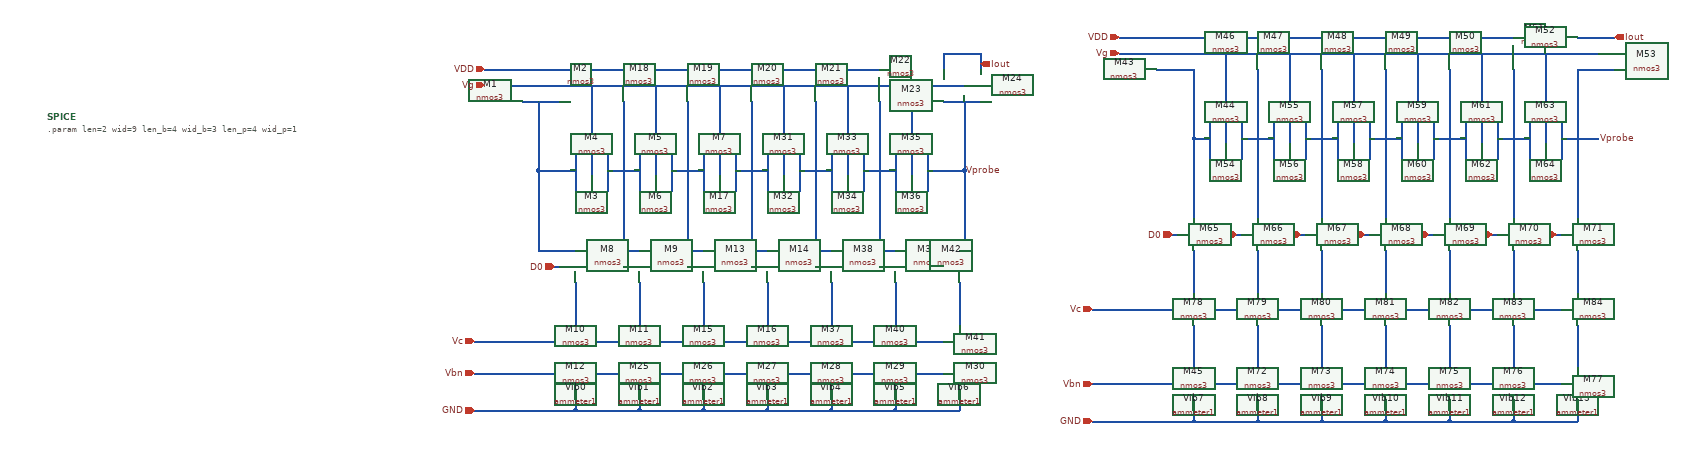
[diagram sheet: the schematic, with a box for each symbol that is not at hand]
v {xschem version=3.4.8RC file_version=1.3}
G {}
K {}
V {}
S {}
F {}
E {}
N 470 -350 480 -350 {lab=D0}
N 590 -350 600 -350 {lab=D1}
N 710 -350 720 -350 {lab=D2}
N 830 -350 840 -350 {lab=D3}
N 510 -320 510 -300 {lab=#net1}
N 630 -320 630 -300 {lab=#net2}
N 750 -320 750 -300 {lab=#net3}
N 870 -320 870 -300 {lab=#net4}
N 430 -150 480 -150 {lab=Vbn}
N 480 -150 600 -150 {lab=Vbn}
N 600 -150 720 -150 {lab=Vbn}
N 720 -150 840 -150 {lab=Vbn}
N 440 -690 450 -690 {lab=Vg}
N 410 -660 480 -660 {lab=#net5}
N 1230 -690 1240 -690 {lab=Vg}
N 1200 -750 1270 -750 {lab=Iout}
N 1200 -660 1270 -660 {lab=Vprobe}
N 450 -690 630 -690 {lab=Vg}
N 630 -690 750 -690 {lab=Vg}
N 1110 -690 1230 -690 {lab=Vg}
N 540 -530 540 -520 {lab=Vg}
N 540 -690 540 -530 {lab=Vg}
N 660 -690 660 -530 {lab=Vg}
N 1140 -530 1140 -520 {lab=Vg}
N 1140 -690 1140 -530 {lab=Vg}
N 510 -560 510 -490 {lab=#net5}
N 570 -560 570 -490 {lab=#net6}
N 1110 -560 1110 -490 {lab=#net7}
N 1170 -560 1170 -490 {lab=Vprobe}
N 440 -660 440 -530 {lab=#net5}
N 440 -530 510 -530 {lab=#net5}
N 570 -530 630 -530 {lab=#net6}
N 600 -660 600 -530 {lab=#net6}
N 690 -530 750 -530 {lab=#net8}
N 720 -660 720 -530 {lab=#net8}
N 1170 -530 1240 -530 {lab=Vprobe}
N 1240 -660 1240 -530 {lab=Vprobe}
N 440 -530 440 -380 {lab=#net5}
N 440 -380 510 -380 {lab=#net5}
N 600 -530 600 -380 {lab=#net6}
N 600 -380 630 -380 {lab=#net6}
N 720 -530 720 -380 {lab=#net8}
N 720 -380 750 -380 {lab=#net8}
N 1240 -530 1240 -380 {lab=Vprobe}
N 1230 -380 1240 -380 {lab=Vprobe}
N 950 -350 960 -350 {lab=D4}
N 990 -320 990 -300 {lab=#net9}
N 1070 -350 1080 -350 {lab=D5}
N 1110 -320 1110 -300 {lab=#net10}
N 1190 -350 1200 -350 {lab=D6}
N 1230 -320 1230 -300 {lab=#net11}
N 750 -690 870 -690 {lab=Vg}
N 870 -690 990 -690 {lab=Vg}
N 990 -690 1110 -690 {lab=Vg}
N 780 -530 780 -520 {lab=Vg}
N 750 -560 750 -490 {lab=#net8}
N 810 -560 810 -490 {lab=#net12}
N 810 -530 870 -530 {lab=#net12}
N 900 -530 900 -520 {lab=Vg}
N 870 -560 870 -490 {lab=#net12}
N 930 -560 930 -490 {lab=#net13}
N 930 -530 990 -530 {lab=#net13}
N 1020 -530 1020 -520 {lab=Vg}
N 990 -560 990 -490 {lab=#net13}
N 1050 -560 1050 -490 {lab=#net7}
N 1050 -530 1110 -530 {lab=#net7}
N 840 -660 840 -530 {lab=#net12}
N 840 -530 840 -380 {lab=#net12}
N 840 -380 870 -380 {lab=#net12}
N 960 -660 960 -530 {lab=#net13}
N 960 -530 960 -380 {lab=#net13}
N 960 -380 990 -380 {lab=#net13}
N 1080 -660 1080 -530 {lab=#net7}
N 1080 -530 1080 -380 {lab=#net7}
N 1080 -380 1110 -380 {lab=#net7}
N 840 -150 960 -150 {lab=Vbn}
N 960 -150 1080 -150 {lab=Vbn}
N 1080 -150 1200 -150 {lab=Vbn}
N 780 -690 780 -530 {lab=Vg}
N 900 -690 900 -530 {lab=Vg}
N 1020 -690 1020 -530 {lab=Vg}
N 630 -560 630 -490 {lab=#net6}
N 690 -560 690 -490 {lab=#net8}
N 660 -530 660 -520 {lab=Vg}
N 410 -720 480 -720 {lab=VDD}
N 480 -720 600 -720 {lab=VDD}
N 600 -720 720 -720 {lab=VDD}
N 720 -720 840 -720 {lab=VDD}
N 840 -720 960 -720 {lab=VDD}
N 960 -720 1080 -720 {lab=VDD}
N 340 -720 410 -720 {lab=VDD}
N 1110 -80 1230 -80 {lab=GND}
N 990 -80 1110 -80 {lab=GND}
N 870 -80 990 -80 {lab=GND}
N 750 -80 870 -80 {lab=GND}
N 630 -80 750 -80 {lab=GND}
N 510 -80 630 -80 {lab=GND}
N 320 -80 510 -80 {lab=GND}
N 320 -150 430 -150 {lab=Vbn}
N 1200 -750 1200 -720 {lab=Iout}
N 1270 -750 1270 -720 {lab=Iout}
N 340 -690 440 -690 {lab=Vg}
N 510 -120 510 -100 {lab=#net14}
N 510 -90 510 -80 {lab=GND}
N 630 -120 630 -100 {lab=#net15}
N 630 -90 630 -80 {lab=GND}
N 750 -120 750 -100 {lab=#net16}
N 750 -90 750 -80 {lab=GND}
N 870 -120 870 -100 {lab=#net17}
N 870 -90 870 -80 {lab=GND}
N 990 -120 990 -100 {lab=#net18}
N 990 -90 990 -80 {lab=GND}
N 1110 -120 1110 -100 {lab=#net19}
N 1110 -90 1110 -80 {lab=GND}
N 1230 -120 1230 -100 {lab=#net20}
N 1230 -90 1230 -80 {lab=GND}
N 1230 -300 1230 -270 {lab=#net11}
N 1110 -300 1110 -270 {lab=#net10}
N 990 -300 990 -270 {lab=#net9}
N 870 -300 870 -270 {lab=#net4}
N 750 -300 750 -270 {lab=#net3}
N 630 -300 630 -270 {lab=#net2}
N 510 -300 510 -270 {lab=#net1}
N 510 -270 510 -240 {lab=#net1}
N 630 -270 630 -240 {lab=#net2}
N 750 -270 750 -240 {lab=#net3}
N 870 -270 870 -240 {lab=#net4}
N 990 -270 990 -240 {lab=#net9}
N 1110 -270 1110 -240 {lab=#net10}
N 1230 -270 1230 -240 {lab=#net11}
N 320 -210 480 -210 {lab=Vc}
N 480 -210 600 -210 {lab=Vc}
N 600 -210 720 -210 {lab=Vc}
N 720 -210 840 -210 {lab=Vc}
N 840 -210 960 -210 {lab=Vc}
N 960 -210 1080 -210 {lab=Vc}
N 1080 -210 1200 -210 {lab=Vc}
N 1630 -410 1640 -410 {lab=D0}
N 1750 -410 1760 -410 {lab=D1}
N 1870 -410 1880 -410 {lab=D2}
N 1990 -410 2000 -410 {lab=D3}
N 1590 -130 1640 -130 {lab=Vbn}
N 1640 -130 1760 -130 {lab=Vbn}
N 1760 -130 1880 -130 {lab=Vbn}
N 1880 -130 2000 -130 {lab=Vbn}
N 1630 -750 1640 -750 {lab=Vg}
N 1600 -720 1670 -720 {lab=#net1}
N 2420 -750 2430 -750 {lab=Vg}
N 2390 -780 2460 -780 {lab=Iout}
N 2390 -720 2460 -720 {lab=Vprobe}
N 1640 -750 1820 -750 {lab=Vg}
N 1820 -750 1940 -750 {lab=Vg}
N 2300 -750 2420 -750 {lab=Vg}
N 1730 -590 1730 -580 {lab=Vg}
N 1730 -750 1730 -590 {lab=Vg}
N 1850 -750 1850 -590 {lab=Vg}
N 2330 -590 2330 -580 {lab=Vg}
N 2330 -750 2330 -590 {lab=Vg}
N 1700 -620 1700 -550 {lab=#net1}
N 1760 -620 1760 -550 {lab=#net2}
N 2300 -620 2300 -550 {lab=#net3}
N 2360 -620 2360 -550 {lab=Vprobe}
N 1670 -720 1670 -590 {lab=#net1}
N 1760 -590 1820 -590 {lab=#net2}
N 1790 -720 1790 -590 {lab=#net2}
N 1880 -590 1940 -590 {lab=#net4}
N 1910 -720 1910 -590 {lab=#net4}
N 2360 -590 2430 -590 {lab=Vprobe}
N 1670 -590 1670 -440 {lab=#net1}
N 1790 -590 1790 -440 {lab=#net2}
N 1910 -590 1910 -440 {lab=#net4}
N 2390 -590 2390 -440 {lab=Vprobe}
N 2110 -410 2120 -410 {lab=D4}
N 2230 -410 2240 -410 {lab=D5}
N 2350 -410 2360 -410 {lab=D6}
N 1940 -750 2060 -750 {lab=Vg}
N 2060 -750 2180 -750 {lab=Vg}
N 2180 -750 2300 -750 {lab=Vg}
N 1970 -590 1970 -580 {lab=Vg}
N 1940 -620 1940 -550 {lab=#net4}
N 2000 -620 2000 -550 {lab=#net5}
N 2000 -590 2060 -590 {lab=#net5}
N 2090 -590 2090 -580 {lab=Vg}
N 2060 -620 2060 -550 {lab=#net5}
N 2120 -620 2120 -550 {lab=#net6}
N 2120 -590 2180 -590 {lab=#net6}
N 2210 -590 2210 -580 {lab=Vg}
N 2180 -620 2180 -550 {lab=#net6}
N 2240 -620 2240 -550 {lab=#net3}
N 2240 -590 2300 -590 {lab=#net3}
N 2030 -720 2030 -590 {lab=#net5}
N 2030 -590 2030 -440 {lab=#net5}
N 2150 -720 2150 -590 {lab=#net6}
N 2150 -590 2150 -440 {lab=#net6}
N 2270 -720 2270 -590 {lab=#net3}
N 2270 -590 2270 -440 {lab=#net3}
N 2000 -130 2120 -130 {lab=Vbn}
N 2120 -130 2240 -130 {lab=Vbn}
N 2240 -130 2360 -130 {lab=Vbn}
N 1970 -750 1970 -590 {lab=Vg}
N 2090 -750 2090 -590 {lab=Vg}
N 2210 -750 2210 -590 {lab=Vg}
N 1820 -620 1820 -550 {lab=#net2}
N 1880 -620 1880 -550 {lab=#net4}
N 1850 -590 1850 -580 {lab=Vg}
N 1600 -780 1670 -780 {lab=VDD}
N 1670 -780 1790 -780 {lab=VDD}
N 1790 -780 1910 -780 {lab=VDD}
N 1910 -780 2030 -780 {lab=VDD}
N 2030 -780 2150 -780 {lab=VDD}
N 2150 -780 2270 -780 {lab=VDD}
N 1530 -780 1600 -780 {lab=VDD}
N 2270 -60 2390 -60 {lab=GND}
N 2150 -60 2270 -60 {lab=GND}
N 2030 -60 2150 -60 {lab=GND}
N 1910 -60 2030 -60 {lab=GND}
N 1790 -60 1910 -60 {lab=GND}
N 1670 -60 1790 -60 {lab=GND}
N 1480 -60 1670 -60 {lab=GND}
N 1480 -130 1590 -130 {lab=Vbn}
N 1530 -750 1630 -750 {lab=Vg}
N 1670 -100 1670 -80 {lab=#net7}
N 1670 -70 1670 -60 {lab=GND}
N 1790 -100 1790 -80 {lab=#net8}
N 1790 -70 1790 -60 {lab=GND}
N 1910 -100 1910 -80 {lab=#net9}
N 1910 -70 1910 -60 {lab=GND}
N 2030 -100 2030 -80 {lab=#net10}
N 2030 -70 2030 -60 {lab=GND}
N 2150 -100 2150 -80 {lab=#net11}
N 2150 -70 2150 -60 {lab=GND}
N 2270 -100 2270 -80 {lab=#net12}
N 2270 -70 2270 -60 {lab=GND}
N 2390 -100 2390 -80 {lab=#net13}
N 2390 -70 2390 -60 {lab=GND}
N 1480 -270 1640 -270 {lab=Vc}
N 1640 -270 1760 -270 {lab=Vc}
N 1760 -270 1880 -270 {lab=Vc}
N 1880 -270 2000 -270 {lab=Vc}
N 2000 -270 2120 -270 {lab=Vc}
N 2120 -270 2240 -270 {lab=Vc}
N 2240 -270 2360 -270 {lab=Vc}
N 2390 -380 2390 -300 {lab=#net14}
N 2270 -380 2270 -300 {lab=#net15}
N 2150 -380 2150 -300 {lab=#net16}
N 2030 -380 2030 -300 {lab=#net17}
N 1910 -380 1910 -300 {lab=#net18}
N 1790 -380 1790 -300 {lab=#net19}
N 1670 -380 1670 -300 {lab=#net20}
N 1670 -240 1670 -160 {lab=#net21}
N 1790 -240 1790 -160 {lab=#net22}
N 1910 -240 1910 -160 {lab=#net23}
N 2030 -240 2030 -160 {lab=#net24}
N 2150 -240 2150 -160 {lab=#net25}
N 2270 -240 2270 -160 {lab=#net26}
N 2390 -240 2390 -160 {lab=#net27}
N 2390 -720 2390 -590 {lab=Vprobe}
N 1670 -590 1700 -590 {lab=#net1}
C {madvlsi/nmos3.sym} 410 -690 2 0 {name=M1
L=\{len\}
W=\{wid\}
body=GND
nf=1
mult=1
ad="'int((nf+1)/2) * W/nf * 0.29'" 
pd="'2*int((nf+1)/2) * (W/nf + 0.29)'"
as="'int((nf+2)/2) * W/nf * 0.29'" 
ps="'2*int((nf+2)/2) * (W/nf + 0.29)'"
nrd="'0.29 / W'" nrs="'0.29 / W'"
sa=0 sb=0 sd=0
model=nfet_01v8
spiceprefix=X
}
C {madvlsi/nmos3.sym} 540 -560 3 0 {name=M4
L=\{len\}
W=\{wid\}
body=GND
nf=1
mult=1
ad="'int((nf+1)/2) * W/nf * 0.29'" 
pd="'2*int((nf+1)/2) * (W/nf + 0.29)'"
as="'int((nf+2)/2) * W/nf * 0.29'" 
ps="'2*int((nf+2)/2) * (W/nf + 0.29)'"
nrd="'0.29 / W'" nrs="'0.29 / W'"
sa=0 sb=0 sd=0
model=nfet_01v8
spiceprefix=X
}
C {madvlsi/nmos3.sym} 510 -150 0 0 {name=M12
L=\{len_b\}
W=\{wid_b\}
body=GND
nf=1
mult=1
ad="'int((nf+1)/2) * W/nf * 0.29'" 
pd="'2*int((nf+1)/2) * (W/nf + 0.29)'"
as="'int((nf+2)/2) * W/nf * 0.29'" 
ps="'2*int((nf+2)/2) * (W/nf + 0.29)'"
nrd="'0.29 / W'" nrs="'0.29 / W'"
sa=0 sb=0 sd=0
model=nfet_01v8
spiceprefix=X
}
C {madvlsi/nmos3.sym} 480 -690 0 0 {name=M2
L=\{len\}
W=\{wid\}
body=GND
nf=1
mult=1
ad="'int((nf+1)/2) * W/nf * 0.29'" 
pd="'2*int((nf+1)/2) * (W/nf + 0.29)'"
as="'int((nf+2)/2) * W/nf * 0.29'" 
ps="'2*int((nf+2)/2) * (W/nf + 0.29)'"
nrd="'0.29 / W'" nrs="'0.29 / W'"
sa=0 sb=0 sd=0
model=nfet_01v8
spiceprefix=X
}
C {madvlsi/nmos3.sym} 600 -690 2 0 {name=M18
L=\{len\}
W=\{wid\}
body=GND
nf=1
mult=1
ad="'int((nf+1)/2) * W/nf * 0.29'" 
pd="'2*int((nf+1)/2) * (W/nf + 0.29)'"
as="'int((nf+2)/2) * W/nf * 0.29'" 
ps="'2*int((nf+2)/2) * (W/nf + 0.29)'"
nrd="'0.29 / W'" nrs="'0.29 / W'"
sa=0 sb=0 sd=0
model=nfet_01v8
spiceprefix=X
}
C {madvlsi/nmos3.sym} 720 -690 2 0 {name=M19
L=\{len\}
W=\{wid\}
body=GND
nf=1
mult=1
ad="'int((nf+1)/2) * W/nf * 0.29'" 
pd="'2*int((nf+1)/2) * (W/nf + 0.29)'"
as="'int((nf+2)/2) * W/nf * 0.29'" 
ps="'2*int((nf+2)/2) * (W/nf + 0.29)'"
nrd="'0.29 / W'" nrs="'0.29 / W'"
sa=0 sb=0 sd=0
model=nfet_01v8
spiceprefix=X
}
C {madvlsi/nmos3.sym} 840 -690 2 0 {name=M20
L=\{len\}
W=\{wid\}
body=GND
nf=1
mult=1
ad="'int((nf+1)/2) * W/nf * 0.29'" 
pd="'2*int((nf+1)/2) * (W/nf + 0.29)'"
as="'int((nf+2)/2) * W/nf * 0.29'" 
ps="'2*int((nf+2)/2) * (W/nf + 0.29)'"
nrd="'0.29 / W'" nrs="'0.29 / W'"
sa=0 sb=0 sd=0
model=nfet_01v8
spiceprefix=X
}
C {madvlsi/nmos3.sym} 960 -690 2 0 {name=M21
L=\{len\}
W=\{wid\}
body=GND
nf=1
mult=1
ad="'int((nf+1)/2) * W/nf * 0.29'" 
pd="'2*int((nf+1)/2) * (W/nf + 0.29)'"
as="'int((nf+2)/2) * W/nf * 0.29'" 
ps="'2*int((nf+2)/2) * (W/nf + 0.29)'"
nrd="'0.29 / W'" nrs="'0.29 / W'"
sa=0 sb=0 sd=0
model=nfet_01v8
spiceprefix=X
}
C {madvlsi/nmos3.sym} 1080 -690 2 0 {name=M22
L=\{len\}
W=\{wid\}
body=GND
nf=1
mult=1
ad="'int((nf+1)/2) * W/nf * 0.29'" 
pd="'2*int((nf+1)/2) * (W/nf + 0.29)'"
as="'int((nf+2)/2) * W/nf * 0.29'" 
ps="'2*int((nf+2)/2) * (W/nf + 0.29)'"
nrd="'0.29 / W'" nrs="'0.29 / W'"
sa=0 sb=0 sd=0
model=nfet_01v8
spiceprefix=X
}
C {madvlsi/nmos3.sym} 1200 -690 2 0 {name=M23
L=\{len\}
W=\{wid\}
body=GND
nf=1
mult=1
ad="'int((nf+1)/2) * W/nf * 0.29'" 
pd="'2*int((nf+1)/2) * (W/nf + 0.29)'"
as="'int((nf+2)/2) * W/nf * 0.29'" 
ps="'2*int((nf+2)/2) * (W/nf + 0.29)'"
nrd="'0.29 / W'" nrs="'0.29 / W'"
sa=0 sb=0 sd=0
model=nfet_01v8
spiceprefix=X
}
C {madvlsi/nmos3.sym} 1270 -690 0 0 {name=M24
L=\{len\}
W=\{wid\}
body=GND
nf=1
mult=1
ad="'int((nf+1)/2) * W/nf * 0.29'" 
pd="'2*int((nf+1)/2) * (W/nf + 0.29)'"
as="'int((nf+2)/2) * W/nf * 0.29'" 
ps="'2*int((nf+2)/2) * (W/nf + 0.29)'"
nrd="'0.29 / W'" nrs="'0.29 / W'"
sa=0 sb=0 sd=0
model=nfet_01v8
spiceprefix=X
}
C {madvlsi/nmos3.sym} 540 -490 1 0 {name=M3
L=\{len\}
W=\{wid\}
body=GND
nf=1
mult=1
ad="'int((nf+1)/2) * W/nf * 0.29'" 
pd="'2*int((nf+1)/2) * (W/nf + 0.29)'"
as="'int((nf+2)/2) * W/nf * 0.29'" 
ps="'2*int((nf+2)/2) * (W/nf + 0.29)'"
nrd="'0.29 / W'" nrs="'0.29 / W'"
sa=0 sb=0 sd=0
model=nfet_01v8
spiceprefix=X
}
C {madvlsi/nmos3.sym} 660 -560 3 0 {name=M5
L=\{len\}
W=\{wid\}
body=GND
nf=1
mult=1
ad="'int((nf+1)/2) * W/nf * 0.29'" 
pd="'2*int((nf+1)/2) * (W/nf + 0.29)'"
as="'int((nf+2)/2) * W/nf * 0.29'" 
ps="'2*int((nf+2)/2) * (W/nf + 0.29)'"
nrd="'0.29 / W'" nrs="'0.29 / W'"
sa=0 sb=0 sd=0
model=nfet_01v8
spiceprefix=X
}
C {madvlsi/nmos3.sym} 660 -490 1 0 {name=M6
L=\{len\}
W=\{wid\}
body=GND
nf=1
mult=1
ad="'int((nf+1)/2) * W/nf * 0.29'" 
pd="'2*int((nf+1)/2) * (W/nf + 0.29)'"
as="'int((nf+2)/2) * W/nf * 0.29'" 
ps="'2*int((nf+2)/2) * (W/nf + 0.29)'"
nrd="'0.29 / W'" nrs="'0.29 / W'"
sa=0 sb=0 sd=0
model=nfet_01v8
spiceprefix=X
}
C {madvlsi/nmos3.sym} 780 -560 3 0 {name=M7
L=\{len\}
W=\{wid\}
body=GND
nf=1
mult=1
ad="'int((nf+1)/2) * W/nf * 0.29'" 
pd="'2*int((nf+1)/2) * (W/nf + 0.29)'"
as="'int((nf+2)/2) * W/nf * 0.29'" 
ps="'2*int((nf+2)/2) * (W/nf + 0.29)'"
nrd="'0.29 / W'" nrs="'0.29 / W'"
sa=0 sb=0 sd=0
model=nfet_01v8
spiceprefix=X
}
C {madvlsi/nmos3.sym} 780 -490 1 0 {name=M17
L=\{len\}
W=\{wid\}
body=GND
nf=1
mult=1
ad="'int((nf+1)/2) * W/nf * 0.29'" 
pd="'2*int((nf+1)/2) * (W/nf + 0.29)'"
as="'int((nf+2)/2) * W/nf * 0.29'" 
ps="'2*int((nf+2)/2) * (W/nf + 0.29)'"
nrd="'0.29 / W'" nrs="'0.29 / W'"
sa=0 sb=0 sd=0
model=nfet_01v8
spiceprefix=X
}
C {madvlsi/nmos3.sym} 900 -560 3 0 {name=M31
L=\{len\}
W=\{wid\}
body=GND
nf=1
mult=1
ad="'int((nf+1)/2) * W/nf * 0.29'" 
pd="'2*int((nf+1)/2) * (W/nf + 0.29)'"
as="'int((nf+2)/2) * W/nf * 0.29'" 
ps="'2*int((nf+2)/2) * (W/nf + 0.29)'"
nrd="'0.29 / W'" nrs="'0.29 / W'"
sa=0 sb=0 sd=0
model=nfet_01v8
spiceprefix=X
}
C {madvlsi/nmos3.sym} 900 -490 1 0 {name=M32
L=\{len\}
W=\{wid\}
body=GND
nf=1
mult=1
ad="'int((nf+1)/2) * W/nf * 0.29'" 
pd="'2*int((nf+1)/2) * (W/nf + 0.29)'"
as="'int((nf+2)/2) * W/nf * 0.29'" 
ps="'2*int((nf+2)/2) * (W/nf + 0.29)'"
nrd="'0.29 / W'" nrs="'0.29 / W'"
sa=0 sb=0 sd=0
model=nfet_01v8
spiceprefix=X
}
C {madvlsi/nmos3.sym} 1020 -560 3 0 {name=M33
L=\{len\}
W=\{wid\}
body=GND
nf=1
mult=1
ad="'int((nf+1)/2) * W/nf * 0.29'" 
pd="'2*int((nf+1)/2) * (W/nf + 0.29)'"
as="'int((nf+2)/2) * W/nf * 0.29'" 
ps="'2*int((nf+2)/2) * (W/nf + 0.29)'"
nrd="'0.29 / W'" nrs="'0.29 / W'"
sa=0 sb=0 sd=0
model=nfet_01v8
spiceprefix=X
}
C {madvlsi/nmos3.sym} 1020 -490 1 0 {name=M34
L=\{len\}
W=\{wid\}
body=GND
nf=1
mult=1
ad="'int((nf+1)/2) * W/nf * 0.29'" 
pd="'2*int((nf+1)/2) * (W/nf + 0.29)'"
as="'int((nf+2)/2) * W/nf * 0.29'" 
ps="'2*int((nf+2)/2) * (W/nf + 0.29)'"
nrd="'0.29 / W'" nrs="'0.29 / W'"
sa=0 sb=0 sd=0
model=nfet_01v8
spiceprefix=X
}
C {madvlsi/nmos3.sym} 1140 -560 3 0 {name=M35
L=\{len\}
W=\{wid\}
body=GND
nf=1
mult=1
ad="'int((nf+1)/2) * W/nf * 0.29'" 
pd="'2*int((nf+1)/2) * (W/nf + 0.29)'"
as="'int((nf+2)/2) * W/nf * 0.29'" 
ps="'2*int((nf+2)/2) * (W/nf + 0.29)'"
nrd="'0.29 / W'" nrs="'0.29 / W'"
sa=0 sb=0 sd=0
model=nfet_01v8
spiceprefix=X
}
C {madvlsi/nmos3.sym} 1140 -490 1 0 {name=M36
L=\{len\}
W=\{wid\}
body=GND
nf=1
mult=1
ad="'int((nf+1)/2) * W/nf * 0.29'" 
pd="'2*int((nf+1)/2) * (W/nf + 0.29)'"
as="'int((nf+2)/2) * W/nf * 0.29'" 
ps="'2*int((nf+2)/2) * (W/nf + 0.29)'"
nrd="'0.29 / W'" nrs="'0.29 / W'"
sa=0 sb=0 sd=0
model=nfet_01v8
spiceprefix=X
}
C {ipin.sym} 320 -150 0 0 {name=p10 lab=Vbn}
C {iopin.sym} 340 -720 2 0 {name=p8 lab=VDD}
C {opin.sym} 1270 -730 0 0 {name=p13 lab=Iout}
C {iopin.sym} 320 -80 2 0 {name=p9 lab=GND}
C {ipin.sym} 470 -350 0 0 {name=p1 lab=D0}
C {ipin.sym} 590 -350 0 0 {name=p2 lab=D1}
C {ipin.sym} 710 -350 0 0 {name=p3 lab=D2}
C {ipin.sym} 830 -350 0 0 {name=p4 lab=D3}
C {ipin.sym} 950 -350 0 0 {name=p5 lab=D4}
C {ipin.sym} 1070 -350 0 0 {name=p6 lab=D5}
C {ipin.sym} 1190 -350 0 0 {name=p7 lab=D6}
C {ipin.sym} 340 -690 0 0 {name=p11 lab=Vg}
C {madvlsi/ammeter1.sym} 510 -100 0 0 {name=Vib0}
C {code_shown.sym} -480 -630 0 0 {name=SPICE only_toplevel=false value=".param len=2 wid=9 len_b=4 wid_b=3 len_p=4 wid_p=1"}
C {madvlsi/ammeter1.sym} 630 -100 0 0 {name=Vib1}
C {madvlsi/ammeter1.sym} 750 -100 0 0 {name=Vib2}
C {madvlsi/ammeter1.sym} 870 -100 0 0 {name=Vib3}
C {madvlsi/ammeter1.sym} 990 -100 0 0 {name=Vib4}
C {madvlsi/ammeter1.sym} 1110 -100 0 0 {name=Vib5}
C {madvlsi/ammeter1.sym} 1230 -100 0 0 {name=Vib6}
C {madvlsi/nmos3.sym} 510 -350 0 0 {name=M8
L=\{len_p\}
W=\{wid_p\}
body=GND
nf=1
mult=1
ad="'int((nf+1)/2) * W/nf * 0.29'" 
pd="'2*int((nf+1)/2) * (W/nf + 0.29)'"
as="'int((nf+2)/2) * W/nf * 0.29'" 
ps="'2*int((nf+2)/2) * (W/nf + 0.29)'"
nrd="'0.29 / W'" nrs="'0.29 / W'"
sa=0 sb=0 sd=0
model=nfet_01v8
spiceprefix=X
}
C {madvlsi/nmos3.sym} 630 -350 0 0 {name=M9
L=\{len_p\}
W=\{wid_p\}
body=GND
nf=1
mult=1
ad="'int((nf+1)/2) * W/nf * 0.29'" 
pd="'2*int((nf+1)/2) * (W/nf + 0.29)'"
as="'int((nf+2)/2) * W/nf * 0.29'" 
ps="'2*int((nf+2)/2) * (W/nf + 0.29)'"
nrd="'0.29 / W'" nrs="'0.29 / W'"
sa=0 sb=0 sd=0
model=nfet_01v8
spiceprefix=X
}
C {madvlsi/nmos3.sym} 750 -350 0 0 {name=M13
L=\{len_p\}
W=\{wid_p\}
body=GND
nf=1
mult=1
ad="'int((nf+1)/2) * W/nf * 0.29'" 
pd="'2*int((nf+1)/2) * (W/nf + 0.29)'"
as="'int((nf+2)/2) * W/nf * 0.29'" 
ps="'2*int((nf+2)/2) * (W/nf + 0.29)'"
nrd="'0.29 / W'" nrs="'0.29 / W'"
sa=0 sb=0 sd=0
model=nfet_01v8
spiceprefix=X
}
C {madvlsi/nmos3.sym} 870 -350 0 0 {name=M14
L=\{len_p\}
W=\{wid_p\}
body=GND
nf=1
mult=1
ad="'int((nf+1)/2) * W/nf * 0.29'" 
pd="'2*int((nf+1)/2) * (W/nf + 0.29)'"
as="'int((nf+2)/2) * W/nf * 0.29'" 
ps="'2*int((nf+2)/2) * (W/nf + 0.29)'"
nrd="'0.29 / W'" nrs="'0.29 / W'"
sa=0 sb=0 sd=0
model=nfet_01v8
spiceprefix=X
}
C {madvlsi/nmos3.sym} 990 -350 0 0 {name=M38
L=\{len_p\}
W=\{wid_p\}
body=GND
nf=1
mult=1
ad="'int((nf+1)/2) * W/nf * 0.29'" 
pd="'2*int((nf+1)/2) * (W/nf + 0.29)'"
as="'int((nf+2)/2) * W/nf * 0.29'" 
ps="'2*int((nf+2)/2) * (W/nf + 0.29)'"
nrd="'0.29 / W'" nrs="'0.29 / W'"
sa=0 sb=0 sd=0
model=nfet_01v8
spiceprefix=X
}
C {madvlsi/nmos3.sym} 1110 -350 0 0 {name=M39
L=\{len_p\}
W=\{wid_p\}
body=GND
nf=1
mult=1
ad="'int((nf+1)/2) * W/nf * 0.29'" 
pd="'2*int((nf+1)/2) * (W/nf + 0.29)'"
as="'int((nf+2)/2) * W/nf * 0.29'" 
ps="'2*int((nf+2)/2) * (W/nf + 0.29)'"
nrd="'0.29 / W'" nrs="'0.29 / W'"
sa=0 sb=0 sd=0
model=nfet_01v8
spiceprefix=X
}
C {madvlsi/nmos3.sym} 1230 -350 0 0 {name=M42
L=\{len_p\}
W=\{wid_p\}
body=GND
nf=1
mult=1
ad="'int((nf+1)/2) * W/nf * 0.29'" 
pd="'2*int((nf+1)/2) * (W/nf + 0.29)'"
as="'int((nf+2)/2) * W/nf * 0.29'" 
ps="'2*int((nf+2)/2) * (W/nf + 0.29)'"
nrd="'0.29 / W'" nrs="'0.29 / W'"
sa=0 sb=0 sd=0
model=nfet_01v8
spiceprefix=X
}
C {madvlsi/nmos3.sym} 630 -150 0 0 {name=M25
L=\{len_b\}
W=\{wid_b\}
body=GND
nf=1
mult=1
ad="'int((nf+1)/2) * W/nf * 0.29'" 
pd="'2*int((nf+1)/2) * (W/nf + 0.29)'"
as="'int((nf+2)/2) * W/nf * 0.29'" 
ps="'2*int((nf+2)/2) * (W/nf + 0.29)'"
nrd="'0.29 / W'" nrs="'0.29 / W'"
sa=0 sb=0 sd=0
model=nfet_01v8
spiceprefix=X
}
C {madvlsi/nmos3.sym} 750 -150 0 0 {name=M26
L=\{len_b\}
W=\{wid_b\}
body=GND
nf=1
mult=1
ad="'int((nf+1)/2) * W/nf * 0.29'" 
pd="'2*int((nf+1)/2) * (W/nf + 0.29)'"
as="'int((nf+2)/2) * W/nf * 0.29'" 
ps="'2*int((nf+2)/2) * (W/nf + 0.29)'"
nrd="'0.29 / W'" nrs="'0.29 / W'"
sa=0 sb=0 sd=0
model=nfet_01v8
spiceprefix=X
}
C {madvlsi/nmos3.sym} 870 -150 0 0 {name=M27
L=\{len_b\}
W=\{wid_b\}
body=GND
nf=1
mult=1
ad="'int((nf+1)/2) * W/nf * 0.29'" 
pd="'2*int((nf+1)/2) * (W/nf + 0.29)'"
as="'int((nf+2)/2) * W/nf * 0.29'" 
ps="'2*int((nf+2)/2) * (W/nf + 0.29)'"
nrd="'0.29 / W'" nrs="'0.29 / W'"
sa=0 sb=0 sd=0
model=nfet_01v8
spiceprefix=X
}
C {madvlsi/nmos3.sym} 990 -150 0 0 {name=M28
L=\{len_b\}
W=\{wid_b\}
body=GND
nf=1
mult=1
ad="'int((nf+1)/2) * W/nf * 0.29'" 
pd="'2*int((nf+1)/2) * (W/nf + 0.29)'"
as="'int((nf+2)/2) * W/nf * 0.29'" 
ps="'2*int((nf+2)/2) * (W/nf + 0.29)'"
nrd="'0.29 / W'" nrs="'0.29 / W'"
sa=0 sb=0 sd=0
model=nfet_01v8
spiceprefix=X
}
C {madvlsi/nmos3.sym} 1110 -150 0 0 {name=M29
L=\{len_b\}
W=\{wid_b\}
body=GND
nf=1
mult=1
ad="'int((nf+1)/2) * W/nf * 0.29'" 
pd="'2*int((nf+1)/2) * (W/nf + 0.29)'"
as="'int((nf+2)/2) * W/nf * 0.29'" 
ps="'2*int((nf+2)/2) * (W/nf + 0.29)'"
nrd="'0.29 / W'" nrs="'0.29 / W'"
sa=0 sb=0 sd=0
model=nfet_01v8
spiceprefix=X
}
C {madvlsi/nmos3.sym} 1230 -150 0 0 {name=M30
L=\{len_b\}
W=\{wid_b\}
body=GND
nf=1
mult=1
ad="'int((nf+1)/2) * W/nf * 0.29'" 
pd="'2*int((nf+1)/2) * (W/nf + 0.29)'"
as="'int((nf+2)/2) * W/nf * 0.29'" 
ps="'2*int((nf+2)/2) * (W/nf + 0.29)'"
nrd="'0.29 / W'" nrs="'0.29 / W'"
sa=0 sb=0 sd=0
model=nfet_01v8
spiceprefix=X
}
C {lab_pin.sym} 1240 -530 2 0 {name=p12 sig_type=std_logic lab=Vprobe}
C {madvlsi/nmos3.sym} 510 -210 0 0 {name=M10
L=\{len_b\}
W=\{wid_b\}
body=GND
nf=1
mult=1
ad="'int((nf+1)/2) * W/nf * 0.29'" 
pd="'2*int((nf+1)/2) * (W/nf + 0.29)'"
as="'int((nf+2)/2) * W/nf * 0.29'" 
ps="'2*int((nf+2)/2) * (W/nf + 0.29)'"
nrd="'0.29 / W'" nrs="'0.29 / W'"
sa=0 sb=0 sd=0
model=nfet_01v8
spiceprefix=X
}
C {madvlsi/nmos3.sym} 630 -210 0 0 {name=M11
L=\{len_b\}
W=\{wid_b\}
body=GND
nf=1
mult=1
ad="'int((nf+1)/2) * W/nf * 0.29'" 
pd="'2*int((nf+1)/2) * (W/nf + 0.29)'"
as="'int((nf+2)/2) * W/nf * 0.29'" 
ps="'2*int((nf+2)/2) * (W/nf + 0.29)'"
nrd="'0.29 / W'" nrs="'0.29 / W'"
sa=0 sb=0 sd=0
model=nfet_01v8
spiceprefix=X
}
C {madvlsi/nmos3.sym} 750 -210 0 0 {name=M15
L=\{len_b\}
W=\{wid_b\}
body=GND
nf=1
mult=1
ad="'int((nf+1)/2) * W/nf * 0.29'" 
pd="'2*int((nf+1)/2) * (W/nf + 0.29)'"
as="'int((nf+2)/2) * W/nf * 0.29'" 
ps="'2*int((nf+2)/2) * (W/nf + 0.29)'"
nrd="'0.29 / W'" nrs="'0.29 / W'"
sa=0 sb=0 sd=0
model=nfet_01v8
spiceprefix=X
}
C {madvlsi/nmos3.sym} 870 -210 0 0 {name=M16
L=\{len_b\}
W=\{wid_b\}
body=GND
nf=1
mult=1
ad="'int((nf+1)/2) * W/nf * 0.29'" 
pd="'2*int((nf+1)/2) * (W/nf + 0.29)'"
as="'int((nf+2)/2) * W/nf * 0.29'" 
ps="'2*int((nf+2)/2) * (W/nf + 0.29)'"
nrd="'0.29 / W'" nrs="'0.29 / W'"
sa=0 sb=0 sd=0
model=nfet_01v8
spiceprefix=X
}
C {madvlsi/nmos3.sym} 990 -210 0 0 {name=M37
L=\{len_b\}
W=\{wid_b\}
body=GND
nf=1
mult=1
ad="'int((nf+1)/2) * W/nf * 0.29'" 
pd="'2*int((nf+1)/2) * (W/nf + 0.29)'"
as="'int((nf+2)/2) * W/nf * 0.29'" 
ps="'2*int((nf+2)/2) * (W/nf + 0.29)'"
nrd="'0.29 / W'" nrs="'0.29 / W'"
sa=0 sb=0 sd=0
model=nfet_01v8
spiceprefix=X
}
C {madvlsi/nmos3.sym} 1110 -210 0 0 {name=M40
L=\{len_b\}
W=\{wid_b\}
body=GND
nf=1
mult=1
ad="'int((nf+1)/2) * W/nf * 0.29'" 
pd="'2*int((nf+1)/2) * (W/nf + 0.29)'"
as="'int((nf+2)/2) * W/nf * 0.29'" 
ps="'2*int((nf+2)/2) * (W/nf + 0.29)'"
nrd="'0.29 / W'" nrs="'0.29 / W'"
sa=0 sb=0 sd=0
model=nfet_01v8
spiceprefix=X
}
C {madvlsi/nmos3.sym} 1230 -210 0 0 {name=M41
L=\{len_b\}
W=\{wid_b\}
body=GND
nf=1
mult=1
ad="'int((nf+1)/2) * W/nf * 0.29'" 
pd="'2*int((nf+1)/2) * (W/nf + 0.29)'"
as="'int((nf+2)/2) * W/nf * 0.29'" 
ps="'2*int((nf+2)/2) * (W/nf + 0.29)'"
nrd="'0.29 / W'" nrs="'0.29 / W'"
sa=0 sb=0 sd=0
model=nfet_01v8
spiceprefix=X
}
C {ipin.sym} 320 -210 0 0 {name=p14 lab=Vc}
C {madvlsi/nmos3.sym} 1600 -750 2 0 {name=M43
L=\{len\}
W=\{wid\}
body=GND
nf=1
mult=1
ad="'int((nf+1)/2) * W/nf * 0.29'" 
pd="'2*int((nf+1)/2) * (W/nf + 0.29)'"
as="'int((nf+2)/2) * W/nf * 0.29'" 
ps="'2*int((nf+2)/2) * (W/nf + 0.29)'"
nrd="'0.29 / W'" nrs="'0.29 / W'"
sa=0 sb=0 sd=0
model=nfet_01v8
spiceprefix=X
}
C {madvlsi/nmos3.sym} 1730 -620 3 0 {name=M44
L=\{len\}
W=\{wid\}
body=GND
nf=1
mult=1
ad="'int((nf+1)/2) * W/nf * 0.29'" 
pd="'2*int((nf+1)/2) * (W/nf + 0.29)'"
as="'int((nf+2)/2) * W/nf * 0.29'" 
ps="'2*int((nf+2)/2) * (W/nf + 0.29)'"
nrd="'0.29 / W'" nrs="'0.29 / W'"
sa=0 sb=0 sd=0
model=nfet_01v8
spiceprefix=X
}
C {madvlsi/nmos3.sym} 1670 -130 0 0 {name=M45
L=\{len_b\}
W=\{wid_b\}
body=GND
nf=1
mult=1
ad="'int((nf+1)/2) * W/nf * 0.29'" 
pd="'2*int((nf+1)/2) * (W/nf + 0.29)'"
as="'int((nf+2)/2) * W/nf * 0.29'" 
ps="'2*int((nf+2)/2) * (W/nf + 0.29)'"
nrd="'0.29 / W'" nrs="'0.29 / W'"
sa=0 sb=0 sd=0
model=nfet_01v8
spiceprefix=X
}
C {madvlsi/nmos3.sym} 1670 -750 0 0 {name=M46
L=\{len\}
W=\{wid\}
body=GND
nf=1
mult=1
ad="'int((nf+1)/2) * W/nf * 0.29'" 
pd="'2*int((nf+1)/2) * (W/nf + 0.29)'"
as="'int((nf+2)/2) * W/nf * 0.29'" 
ps="'2*int((nf+2)/2) * (W/nf + 0.29)'"
nrd="'0.29 / W'" nrs="'0.29 / W'"
sa=0 sb=0 sd=0
model=nfet_01v8
spiceprefix=X
}
C {madvlsi/nmos3.sym} 1790 -750 2 0 {name=M47
L=\{len\}
W=\{wid\}
body=GND
nf=1
mult=1
ad="'int((nf+1)/2) * W/nf * 0.29'" 
pd="'2*int((nf+1)/2) * (W/nf + 0.29)'"
as="'int((nf+2)/2) * W/nf * 0.29'" 
ps="'2*int((nf+2)/2) * (W/nf + 0.29)'"
nrd="'0.29 / W'" nrs="'0.29 / W'"
sa=0 sb=0 sd=0
model=nfet_01v8
spiceprefix=X
}
C {madvlsi/nmos3.sym} 1910 -750 2 0 {name=M48
L=\{len\}
W=\{wid\}
body=GND
nf=1
mult=1
ad="'int((nf+1)/2) * W/nf * 0.29'" 
pd="'2*int((nf+1)/2) * (W/nf + 0.29)'"
as="'int((nf+2)/2) * W/nf * 0.29'" 
ps="'2*int((nf+2)/2) * (W/nf + 0.29)'"
nrd="'0.29 / W'" nrs="'0.29 / W'"
sa=0 sb=0 sd=0
model=nfet_01v8
spiceprefix=X
}
C {madvlsi/nmos3.sym} 2030 -750 2 0 {name=M49
L=\{len\}
W=\{wid\}
body=GND
nf=1
mult=1
ad="'int((nf+1)/2) * W/nf * 0.29'" 
pd="'2*int((nf+1)/2) * (W/nf + 0.29)'"
as="'int((nf+2)/2) * W/nf * 0.29'" 
ps="'2*int((nf+2)/2) * (W/nf + 0.29)'"
nrd="'0.29 / W'" nrs="'0.29 / W'"
sa=0 sb=0 sd=0
model=nfet_01v8
spiceprefix=X
}
C {madvlsi/nmos3.sym} 2150 -750 2 0 {name=M50
L=\{len\}
W=\{wid\}
body=GND
nf=1
mult=1
ad="'int((nf+1)/2) * W/nf * 0.29'" 
pd="'2*int((nf+1)/2) * (W/nf + 0.29)'"
as="'int((nf+2)/2) * W/nf * 0.29'" 
ps="'2*int((nf+2)/2) * (W/nf + 0.29)'"
nrd="'0.29 / W'" nrs="'0.29 / W'"
sa=0 sb=0 sd=0
model=nfet_01v8
spiceprefix=X
}
C {madvlsi/nmos3.sym} 2270 -750 2 0 {name=M51
L=\{len\}
W=\{wid\}
body=GND
nf=1
mult=1
ad="'int((nf+1)/2) * W/nf * 0.29'" 
pd="'2*int((nf+1)/2) * (W/nf + 0.29)'"
as="'int((nf+2)/2) * W/nf * 0.29'" 
ps="'2*int((nf+2)/2) * (W/nf + 0.29)'"
nrd="'0.29 / W'" nrs="'0.29 / W'"
sa=0 sb=0 sd=0
model=nfet_01v8
spiceprefix=X
}
C {madvlsi/nmos3.sym} 2390 -750 2 0 {name=M52
L=\{len\}
W=\{wid\}
body=GND
nf=1
mult=1
ad="'int((nf+1)/2) * W/nf * 0.29'" 
pd="'2*int((nf+1)/2) * (W/nf + 0.29)'"
as="'int((nf+2)/2) * W/nf * 0.29'" 
ps="'2*int((nf+2)/2) * (W/nf + 0.29)'"
nrd="'0.29 / W'" nrs="'0.29 / W'"
sa=0 sb=0 sd=0
model=nfet_01v8
spiceprefix=X
}
C {madvlsi/nmos3.sym} 2460 -750 0 0 {name=M53
L=\{len\}
W=\{wid\}
body=GND
nf=1
mult=1
ad="'int((nf+1)/2) * W/nf * 0.29'" 
pd="'2*int((nf+1)/2) * (W/nf + 0.29)'"
as="'int((nf+2)/2) * W/nf * 0.29'" 
ps="'2*int((nf+2)/2) * (W/nf + 0.29)'"
nrd="'0.29 / W'" nrs="'0.29 / W'"
sa=0 sb=0 sd=0
model=nfet_01v8
spiceprefix=X
}
C {madvlsi/nmos3.sym} 1730 -550 1 0 {name=M54
L=\{len\}
W=\{wid\}
body=GND
nf=1
mult=1
ad="'int((nf+1)/2) * W/nf * 0.29'" 
pd="'2*int((nf+1)/2) * (W/nf + 0.29)'"
as="'int((nf+2)/2) * W/nf * 0.29'" 
ps="'2*int((nf+2)/2) * (W/nf + 0.29)'"
nrd="'0.29 / W'" nrs="'0.29 / W'"
sa=0 sb=0 sd=0
model=nfet_01v8
spiceprefix=X
}
C {madvlsi/nmos3.sym} 1850 -620 3 0 {name=M55
L=\{len\}
W=\{wid\}
body=GND
nf=1
mult=1
ad="'int((nf+1)/2) * W/nf * 0.29'" 
pd="'2*int((nf+1)/2) * (W/nf + 0.29)'"
as="'int((nf+2)/2) * W/nf * 0.29'" 
ps="'2*int((nf+2)/2) * (W/nf + 0.29)'"
nrd="'0.29 / W'" nrs="'0.29 / W'"
sa=0 sb=0 sd=0
model=nfet_01v8
spiceprefix=X
}
C {madvlsi/nmos3.sym} 1850 -550 1 0 {name=M56
L=\{len\}
W=\{wid\}
body=GND
nf=1
mult=1
ad="'int((nf+1)/2) * W/nf * 0.29'" 
pd="'2*int((nf+1)/2) * (W/nf + 0.29)'"
as="'int((nf+2)/2) * W/nf * 0.29'" 
ps="'2*int((nf+2)/2) * (W/nf + 0.29)'"
nrd="'0.29 / W'" nrs="'0.29 / W'"
sa=0 sb=0 sd=0
model=nfet_01v8
spiceprefix=X
}
C {madvlsi/nmos3.sym} 1970 -620 3 0 {name=M57
L=\{len\}
W=\{wid\}
body=GND
nf=1
mult=1
ad="'int((nf+1)/2) * W/nf * 0.29'" 
pd="'2*int((nf+1)/2) * (W/nf + 0.29)'"
as="'int((nf+2)/2) * W/nf * 0.29'" 
ps="'2*int((nf+2)/2) * (W/nf + 0.29)'"
nrd="'0.29 / W'" nrs="'0.29 / W'"
sa=0 sb=0 sd=0
model=nfet_01v8
spiceprefix=X
}
C {madvlsi/nmos3.sym} 1970 -550 1 0 {name=M58
L=\{len\}
W=\{wid\}
body=GND
nf=1
mult=1
ad="'int((nf+1)/2) * W/nf * 0.29'" 
pd="'2*int((nf+1)/2) * (W/nf + 0.29)'"
as="'int((nf+2)/2) * W/nf * 0.29'" 
ps="'2*int((nf+2)/2) * (W/nf + 0.29)'"
nrd="'0.29 / W'" nrs="'0.29 / W'"
sa=0 sb=0 sd=0
model=nfet_01v8
spiceprefix=X
}
C {madvlsi/nmos3.sym} 2090 -620 3 0 {name=M59
L=\{len\}
W=\{wid\}
body=GND
nf=1
mult=1
ad="'int((nf+1)/2) * W/nf * 0.29'" 
pd="'2*int((nf+1)/2) * (W/nf + 0.29)'"
as="'int((nf+2)/2) * W/nf * 0.29'" 
ps="'2*int((nf+2)/2) * (W/nf + 0.29)'"
nrd="'0.29 / W'" nrs="'0.29 / W'"
sa=0 sb=0 sd=0
model=nfet_01v8
spiceprefix=X
}
C {madvlsi/nmos3.sym} 2090 -550 1 0 {name=M60
L=\{len\}
W=\{wid\}
body=GND
nf=1
mult=1
ad="'int((nf+1)/2) * W/nf * 0.29'" 
pd="'2*int((nf+1)/2) * (W/nf + 0.29)'"
as="'int((nf+2)/2) * W/nf * 0.29'" 
ps="'2*int((nf+2)/2) * (W/nf + 0.29)'"
nrd="'0.29 / W'" nrs="'0.29 / W'"
sa=0 sb=0 sd=0
model=nfet_01v8
spiceprefix=X
}
C {madvlsi/nmos3.sym} 2210 -620 3 0 {name=M61
L=\{len\}
W=\{wid\}
body=GND
nf=1
mult=1
ad="'int((nf+1)/2) * W/nf * 0.29'" 
pd="'2*int((nf+1)/2) * (W/nf + 0.29)'"
as="'int((nf+2)/2) * W/nf * 0.29'" 
ps="'2*int((nf+2)/2) * (W/nf + 0.29)'"
nrd="'0.29 / W'" nrs="'0.29 / W'"
sa=0 sb=0 sd=0
model=nfet_01v8
spiceprefix=X
}
C {madvlsi/nmos3.sym} 2210 -550 1 0 {name=M62
L=\{len\}
W=\{wid\}
body=GND
nf=1
mult=1
ad="'int((nf+1)/2) * W/nf * 0.29'" 
pd="'2*int((nf+1)/2) * (W/nf + 0.29)'"
as="'int((nf+2)/2) * W/nf * 0.29'" 
ps="'2*int((nf+2)/2) * (W/nf + 0.29)'"
nrd="'0.29 / W'" nrs="'0.29 / W'"
sa=0 sb=0 sd=0
model=nfet_01v8
spiceprefix=X
}
C {madvlsi/nmos3.sym} 2330 -620 3 0 {name=M63
L=\{len\}
W=\{wid\}
body=GND
nf=1
mult=1
ad="'int((nf+1)/2) * W/nf * 0.29'" 
pd="'2*int((nf+1)/2) * (W/nf + 0.29)'"
as="'int((nf+2)/2) * W/nf * 0.29'" 
ps="'2*int((nf+2)/2) * (W/nf + 0.29)'"
nrd="'0.29 / W'" nrs="'0.29 / W'"
sa=0 sb=0 sd=0
model=nfet_01v8
spiceprefix=X
}
C {madvlsi/nmos3.sym} 2330 -550 1 0 {name=M64
L=\{len\}
W=\{wid\}
body=GND
nf=1
mult=1
ad="'int((nf+1)/2) * W/nf * 0.29'" 
pd="'2*int((nf+1)/2) * (W/nf + 0.29)'"
as="'int((nf+2)/2) * W/nf * 0.29'" 
ps="'2*int((nf+2)/2) * (W/nf + 0.29)'"
nrd="'0.29 / W'" nrs="'0.29 / W'"
sa=0 sb=0 sd=0
model=nfet_01v8
spiceprefix=X
}
C {ipin.sym} 1480 -130 0 0 {name=p15 lab=Vbn}
C {iopin.sym} 1530 -780 2 0 {name=p16 lab=VDD}
C {opin.sym} 2460 -780 0 0 {name=p17 lab=Iout}
C {iopin.sym} 1480 -60 2 0 {name=p18 lab=GND}
C {ipin.sym} 1630 -410 0 0 {name=p19 lab=D0}
C {ipin.sym} 1750 -410 0 0 {name=p20 lab=D1}
C {ipin.sym} 1870 -410 0 0 {name=p21 lab=D2}
C {ipin.sym} 1990 -410 0 0 {name=p22 lab=D3}
C {ipin.sym} 2110 -410 0 0 {name=p23 lab=D4}
C {ipin.sym} 2230 -410 0 0 {name=p24 lab=D5}
C {ipin.sym} 2350 -410 0 0 {name=p25 lab=D6}
C {ipin.sym} 1530 -750 0 0 {name=p26 lab=Vg}
C {madvlsi/ammeter1.sym} 1670 -80 0 0 {name=Vib7}
C {madvlsi/ammeter1.sym} 1790 -80 0 0 {name=Vib8}
C {madvlsi/ammeter1.sym} 1910 -80 0 0 {name=Vib9}
C {madvlsi/ammeter1.sym} 2030 -80 0 0 {name=Vib10}
C {madvlsi/ammeter1.sym} 2150 -80 0 0 {name=Vib11}
C {madvlsi/ammeter1.sym} 2270 -80 0 0 {name=Vib12}
C {madvlsi/ammeter1.sym} 2390 -80 0 0 {name=Vib13}
C {madvlsi/nmos3.sym} 1670 -410 0 0 {name=M65
L=\{len_p\}
W=\{wid_p\}
body=GND
nf=1
mult=1
ad="'int((nf+1)/2) * W/nf * 0.29'" 
pd="'2*int((nf+1)/2) * (W/nf + 0.29)'"
as="'int((nf+2)/2) * W/nf * 0.29'" 
ps="'2*int((nf+2)/2) * (W/nf + 0.29)'"
nrd="'0.29 / W'" nrs="'0.29 / W'"
sa=0 sb=0 sd=0
model=nfet_01v8
spiceprefix=X
}
C {madvlsi/nmos3.sym} 1790 -410 0 0 {name=M66
L=\{len_p\}
W=\{wid_p\}
body=GND
nf=1
mult=1
ad="'int((nf+1)/2) * W/nf * 0.29'" 
pd="'2*int((nf+1)/2) * (W/nf + 0.29)'"
as="'int((nf+2)/2) * W/nf * 0.29'" 
ps="'2*int((nf+2)/2) * (W/nf + 0.29)'"
nrd="'0.29 / W'" nrs="'0.29 / W'"
sa=0 sb=0 sd=0
model=nfet_01v8
spiceprefix=X
}
C {madvlsi/nmos3.sym} 1910 -410 0 0 {name=M67
L=\{len_p\}
W=\{wid_p\}
body=GND
nf=1
mult=1
ad="'int((nf+1)/2) * W/nf * 0.29'" 
pd="'2*int((nf+1)/2) * (W/nf + 0.29)'"
as="'int((nf+2)/2) * W/nf * 0.29'" 
ps="'2*int((nf+2)/2) * (W/nf + 0.29)'"
nrd="'0.29 / W'" nrs="'0.29 / W'"
sa=0 sb=0 sd=0
model=nfet_01v8
spiceprefix=X
}
C {madvlsi/nmos3.sym} 2030 -410 0 0 {name=M68
L=\{len_p\}
W=\{wid_p\}
body=GND
nf=1
mult=1
ad="'int((nf+1)/2) * W/nf * 0.29'" 
pd="'2*int((nf+1)/2) * (W/nf + 0.29)'"
as="'int((nf+2)/2) * W/nf * 0.29'" 
ps="'2*int((nf+2)/2) * (W/nf + 0.29)'"
nrd="'0.29 / W'" nrs="'0.29 / W'"
sa=0 sb=0 sd=0
model=nfet_01v8
spiceprefix=X
}
C {madvlsi/nmos3.sym} 2150 -410 0 0 {name=M69
L=\{len_p\}
W=\{wid_p\}
body=GND
nf=1
mult=1
ad="'int((nf+1)/2) * W/nf * 0.29'" 
pd="'2*int((nf+1)/2) * (W/nf + 0.29)'"
as="'int((nf+2)/2) * W/nf * 0.29'" 
ps="'2*int((nf+2)/2) * (W/nf + 0.29)'"
nrd="'0.29 / W'" nrs="'0.29 / W'"
sa=0 sb=0 sd=0
model=nfet_01v8
spiceprefix=X
}
C {madvlsi/nmos3.sym} 2270 -410 0 0 {name=M70
L=\{len_p\}
W=\{wid_p\}
body=GND
nf=1
mult=1
ad="'int((nf+1)/2) * W/nf * 0.29'" 
pd="'2*int((nf+1)/2) * (W/nf + 0.29)'"
as="'int((nf+2)/2) * W/nf * 0.29'" 
ps="'2*int((nf+2)/2) * (W/nf + 0.29)'"
nrd="'0.29 / W'" nrs="'0.29 / W'"
sa=0 sb=0 sd=0
model=nfet_01v8
spiceprefix=X
}
C {madvlsi/nmos3.sym} 2390 -410 0 0 {name=M71
L=\{len_p\}
W=\{wid_p\}
body=GND
nf=1
mult=1
ad="'int((nf+1)/2) * W/nf * 0.29'" 
pd="'2*int((nf+1)/2) * (W/nf + 0.29)'"
as="'int((nf+2)/2) * W/nf * 0.29'" 
ps="'2*int((nf+2)/2) * (W/nf + 0.29)'"
nrd="'0.29 / W'" nrs="'0.29 / W'"
sa=0 sb=0 sd=0
model=nfet_01v8
spiceprefix=X
}
C {madvlsi/nmos3.sym} 1790 -130 0 0 {name=M72
L=\{len_b\}
W=\{wid_b\}
body=GND
nf=1
mult=1
ad="'int((nf+1)/2) * W/nf * 0.29'" 
pd="'2*int((nf+1)/2) * (W/nf + 0.29)'"
as="'int((nf+2)/2) * W/nf * 0.29'" 
ps="'2*int((nf+2)/2) * (W/nf + 0.29)'"
nrd="'0.29 / W'" nrs="'0.29 / W'"
sa=0 sb=0 sd=0
model=nfet_01v8
spiceprefix=X
}
C {madvlsi/nmos3.sym} 1910 -130 0 0 {name=M73
L=\{len_b\}
W=\{wid_b\}
body=GND
nf=1
mult=1
ad="'int((nf+1)/2) * W/nf * 0.29'" 
pd="'2*int((nf+1)/2) * (W/nf + 0.29)'"
as="'int((nf+2)/2) * W/nf * 0.29'" 
ps="'2*int((nf+2)/2) * (W/nf + 0.29)'"
nrd="'0.29 / W'" nrs="'0.29 / W'"
sa=0 sb=0 sd=0
model=nfet_01v8
spiceprefix=X
}
C {madvlsi/nmos3.sym} 2030 -130 0 0 {name=M74
L=\{len_b\}
W=\{wid_b\}
body=GND
nf=1
mult=1
ad="'int((nf+1)/2) * W/nf * 0.29'" 
pd="'2*int((nf+1)/2) * (W/nf + 0.29)'"
as="'int((nf+2)/2) * W/nf * 0.29'" 
ps="'2*int((nf+2)/2) * (W/nf + 0.29)'"
nrd="'0.29 / W'" nrs="'0.29 / W'"
sa=0 sb=0 sd=0
model=nfet_01v8
spiceprefix=X
}
C {madvlsi/nmos3.sym} 2150 -130 0 0 {name=M75
L=\{len_b\}
W=\{wid_b\}
body=GND
nf=1
mult=1
ad="'int((nf+1)/2) * W/nf * 0.29'" 
pd="'2*int((nf+1)/2) * (W/nf + 0.29)'"
as="'int((nf+2)/2) * W/nf * 0.29'" 
ps="'2*int((nf+2)/2) * (W/nf + 0.29)'"
nrd="'0.29 / W'" nrs="'0.29 / W'"
sa=0 sb=0 sd=0
model=nfet_01v8
spiceprefix=X
}
C {madvlsi/nmos3.sym} 2270 -130 0 0 {name=M76
L=\{len_b\}
W=\{wid_b\}
body=GND
nf=1
mult=1
ad="'int((nf+1)/2) * W/nf * 0.29'" 
pd="'2*int((nf+1)/2) * (W/nf + 0.29)'"
as="'int((nf+2)/2) * W/nf * 0.29'" 
ps="'2*int((nf+2)/2) * (W/nf + 0.29)'"
nrd="'0.29 / W'" nrs="'0.29 / W'"
sa=0 sb=0 sd=0
model=nfet_01v8
spiceprefix=X
}
C {madvlsi/nmos3.sym} 2390 -130 0 0 {name=M77
L=\{len_b\}
W=\{wid_b\}
body=GND
nf=1
mult=1
ad="'int((nf+1)/2) * W/nf * 0.29'" 
pd="'2*int((nf+1)/2) * (W/nf + 0.29)'"
as="'int((nf+2)/2) * W/nf * 0.29'" 
ps="'2*int((nf+2)/2) * (W/nf + 0.29)'"
nrd="'0.29 / W'" nrs="'0.29 / W'"
sa=0 sb=0 sd=0
model=nfet_01v8
spiceprefix=X
}
C {lab_pin.sym} 2430 -590 2 0 {name=p27 sig_type=std_logic lab=Vprobe}
C {madvlsi/nmos3.sym} 1670 -270 0 0 {name=M78
L=\{len_b\}
W=\{wid_b\}
body=GND
nf=1
mult=1
ad="'int((nf+1)/2) * W/nf * 0.29'" 
pd="'2*int((nf+1)/2) * (W/nf + 0.29)'"
as="'int((nf+2)/2) * W/nf * 0.29'" 
ps="'2*int((nf+2)/2) * (W/nf + 0.29)'"
nrd="'0.29 / W'" nrs="'0.29 / W'"
sa=0 sb=0 sd=0
model=nfet_01v8
spiceprefix=X
}
C {madvlsi/nmos3.sym} 1790 -270 0 0 {name=M79
L=\{len_b\}
W=\{wid_b\}
body=GND
nf=1
mult=1
ad="'int((nf+1)/2) * W/nf * 0.29'" 
pd="'2*int((nf+1)/2) * (W/nf + 0.29)'"
as="'int((nf+2)/2) * W/nf * 0.29'" 
ps="'2*int((nf+2)/2) * (W/nf + 0.29)'"
nrd="'0.29 / W'" nrs="'0.29 / W'"
sa=0 sb=0 sd=0
model=nfet_01v8
spiceprefix=X
}
C {madvlsi/nmos3.sym} 1910 -270 0 0 {name=M80
L=\{len_b\}
W=\{wid_b\}
body=GND
nf=1
mult=1
ad="'int((nf+1)/2) * W/nf * 0.29'" 
pd="'2*int((nf+1)/2) * (W/nf + 0.29)'"
as="'int((nf+2)/2) * W/nf * 0.29'" 
ps="'2*int((nf+2)/2) * (W/nf + 0.29)'"
nrd="'0.29 / W'" nrs="'0.29 / W'"
sa=0 sb=0 sd=0
model=nfet_01v8
spiceprefix=X
}
C {madvlsi/nmos3.sym} 2030 -270 0 0 {name=M81
L=\{len_b\}
W=\{wid_b\}
body=GND
nf=1
mult=1
ad="'int((nf+1)/2) * W/nf * 0.29'" 
pd="'2*int((nf+1)/2) * (W/nf + 0.29)'"
as="'int((nf+2)/2) * W/nf * 0.29'" 
ps="'2*int((nf+2)/2) * (W/nf + 0.29)'"
nrd="'0.29 / W'" nrs="'0.29 / W'"
sa=0 sb=0 sd=0
model=nfet_01v8
spiceprefix=X
}
C {madvlsi/nmos3.sym} 2150 -270 0 0 {name=M82
L=\{len_b\}
W=\{wid_b\}
body=GND
nf=1
mult=1
ad="'int((nf+1)/2) * W/nf * 0.29'" 
pd="'2*int((nf+1)/2) * (W/nf + 0.29)'"
as="'int((nf+2)/2) * W/nf * 0.29'" 
ps="'2*int((nf+2)/2) * (W/nf + 0.29)'"
nrd="'0.29 / W'" nrs="'0.29 / W'"
sa=0 sb=0 sd=0
model=nfet_01v8
spiceprefix=X
}
C {madvlsi/nmos3.sym} 2270 -270 0 0 {name=M83
L=\{len_b\}
W=\{wid_b\}
body=GND
nf=1
mult=1
ad="'int((nf+1)/2) * W/nf * 0.29'" 
pd="'2*int((nf+1)/2) * (W/nf + 0.29)'"
as="'int((nf+2)/2) * W/nf * 0.29'" 
ps="'2*int((nf+2)/2) * (W/nf + 0.29)'"
nrd="'0.29 / W'" nrs="'0.29 / W'"
sa=0 sb=0 sd=0
model=nfet_01v8
spiceprefix=X
}
C {madvlsi/nmos3.sym} 2390 -270 0 0 {name=M84
L=\{len_b\}
W=\{wid_b\}
body=GND
nf=1
mult=1
ad="'int((nf+1)/2) * W/nf * 0.29'" 
pd="'2*int((nf+1)/2) * (W/nf + 0.29)'"
as="'int((nf+2)/2) * W/nf * 0.29'" 
ps="'2*int((nf+2)/2) * (W/nf + 0.29)'"
nrd="'0.29 / W'" nrs="'0.29 / W'"
sa=0 sb=0 sd=0
model=nfet_01v8
spiceprefix=X
}
C {ipin.sym} 1480 -270 0 0 {name=p28 lab=Vc}
